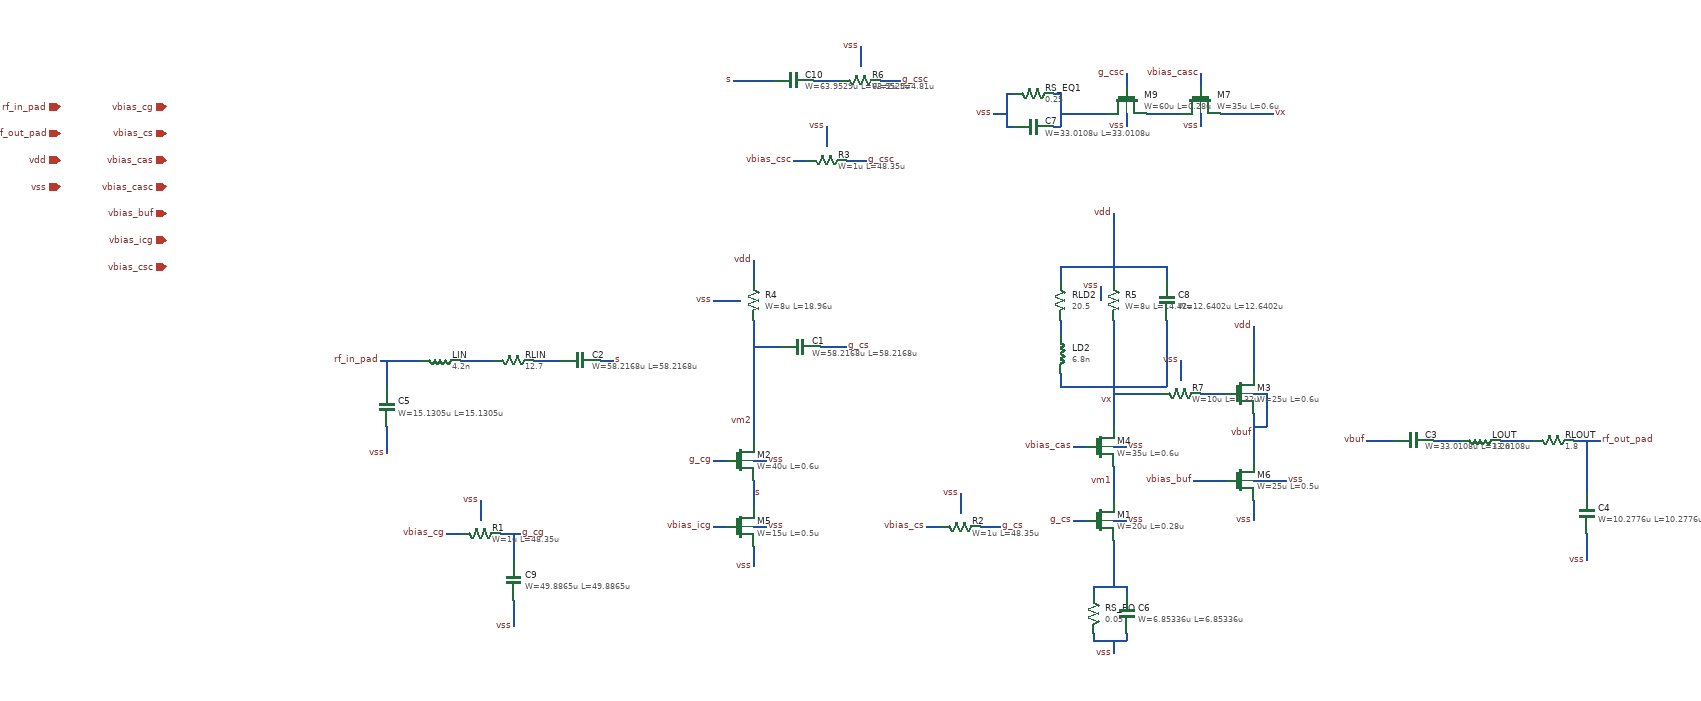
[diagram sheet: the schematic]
v {xschem version=3.4.8RC file_version=1.3}
G {}
K {}
V {}
S {}
F {}
E {}
N 700 -330 720 -330 {
lab=vss}
N 700 -540 700 -460 {
lab=vm2}
N 700 -630 700 -600 {
lab=vdd}
N 470 -480 490 -480 {
lab=s}
N 140 -480 170 -480 {
lab=rf_in_pad}
N 700 -500 740 -500 {
lab=vm2}
N 800 -500 840 -500 {
lab=g_cs}
N 700 -300 700 -290 {
lab=s}
N 700 -290 700 -260 {
lab=s}
N 640 -330 660 -330 {
lab=g_cg}
N 240 -220 260 -220 {
lab=vbias_cg}
N 320 -220 350 -220 {
lab=g_cg}
N 340 -120 340 -80 {
lab=vss}
N 1240 -240 1260 -240 {
lab=vss}
N 1240 -210 1240 -200 {
lab=#net1}
N 1180 -240 1200 -240 {
lab=g_cs}
N 960 -230 980 -230 {
lab=vbias_cs}
N 1040 -230 1070 -230 {
lab=g_cs}
N 1240 -200 1240 -140 {
lab=#net1}
N 1240 -640 1240 -600 {
lab=vdd}
N 1450 -530 1450 -460 {
lab=vdd}
N 1450 -400 1450 -330 {
lab=vbuf}
N 1450 -270 1450 -240 {
lab=vss}
N 1450 -430 1470 -430 {
lab=vbuf}
N 1620 -360 1660 -360 {
lab=vbuf}
N 1720 -360 1760 -360 {
lab=#net2}
N 1820 -360 1870 -360 {
lab=#net3}
N 1930 -360 1970 -360 {
lab=rf_out_pad}
N 1950 -360 1950 -280 {
lab=rf_out_pad}
N 1950 -220 1950 -180 {
lab=vss}
N 150 -480 150 -440 {
lab=rf_in_pad}
N 150 -380 150 -340 {
lab=vss}
N 170 -480 200 -480 {
lab=rf_in_pad}
N 260 -480 310 -480 {
lab=#net4}
N 370 -480 410 -480 {
lab=#net5}
N 1240 -350 1260 -350 {
lab=vss}
N 1240 -320 1240 -310 {
lab=vm1}
N 1180 -350 1200 -350 {
lab=vbias_cas}
N 1240 -540 1240 -460 {
lab=vx}
N 1240 -310 1240 -270 {
lab=vm1}
N 1470 -430 1470 -380 {
lab=vbuf}
N 1450 -380 1470 -380 {
lab=vbuf}
N 700 -230 720 -230 {
lab=vss}
N 700 -200 700 -190 {
lab=vss}
N 640 -230 660 -230 {
lab=vbias_icg}
N 700 -190 700 -170 {
lab=vss}
N 1360 -300 1410 -300 {
lab=vbias_buf}
N 1450 -300 1500 -300 {
lab=vss}
N 1260 -140 1260 -130 {
lab=#net1}
N 1210 -140 1260 -140 {
lab=#net1}
N 1260 -70 1260 -60 {
lab=vss}
N 1210 -60 1260 -60 {
lab=vss}
N 1210 -140 1210 -130 {
lab=#net1}
N 1210 -70 1210 -60 {
lab=vss}
N 1240 -60 1240 -40 {
lab=vss}
N 1370 -430 1410 -430 {
lab=#net6}
N 1240 -430 1310 -430 {
lab=vx}
N 1260 -850 1260 -830 {
lab=vss}
N 1220 -850 1230 -850 {
lab=#net7}
N 1260 -910 1260 -890 {
lab=g_csc}
N 760 -780 780 -780 {
lab=vbias_csc}
N 840 -780 870 -780 {
lab=g_csc}
N 1160 -850 1220 -850 {
lab=#net7}
N 1370 -850 1370 -830 {
lab=vss}
N 1330 -850 1340 -850 {
lab=#net8}
N 1370 -910 1370 -890 {
lab=vbias_casc}
N 1400 -850 1480 -850 {
lab=vx}
N 1290 -850 1330 -850 {
lab=#net8}
N 1150 -830 1160 -830 {
lab=#net7}
N 1160 -880 1160 -830 {
lab=#net7}
N 1080 -830 1090 -830 {
lab=vss}
N 1080 -880 1080 -830 {
lab=vss}
N 1150 -880 1160 -880 {
lab=#net7}
N 1080 -880 1090 -880 {
lab=vss}
N 1060 -850 1080 -850 {
lab=vss}
N 790 -900 830 -900 {
lab=#net9
}
N 700 -400 700 -390 {
lab=vm2}
N 700 -390 700 -360 {lab=vm2}
N 1160 -620 1160 -600 {lab=vdd}
N 1160 -620 1240 -620 {lab=vdd}
N 1160 -540 1160 -520 {lab=#net10}
N 1320 -540 1320 -530 {lab=vx}
N 1240 -440 1320 -440 {lab=vx}
N 1320 -620 1320 -600 {lab=vdd}
N 1240 -620 1320 -620 {lab=vdd}
N 1320 -530 1320 -520 {lab=vx}
N 700 -460 700 -400 {lab=vm2}
N 1240 -460 1240 -380 {lab=vx}
N 1160 -460 1160 -440 {lab=vx}
N 1160 -440 1240 -440 {lab=vx}
N 1320 -520 1320 -440 {lab=vx}
N 890 -900 920 -900 {lab=g_csc
}
N 1010 -280 1010 -250 {lab=vss}
N 810 -830 810 -800 {lab=#net11}
N 290 -270 290 -240 {lab=vss}
N 640 -570 680 -570 {lab=vss}
N 1220 -590 1220 -570 {lab=vss}
N 1240 -700 1240 -640 {lab=vdd}
N 860 -950 860 -920 {lab=vss
}
N 1340 -480 1340 -450 {lab=vss}
N 340 -220 340 -180 {lab=g_cg}
N 670 -900 730 -900 {lab=s
}
C {lab_pin.sym} 700 -630 0 0 {name=p11 sig_type=std_logic lab=vdd
}
C {lab_pin.sym} 840 -500 2 0 {name=p14 sig_type=std_logic lab=g_cs}
C {lab_pin.sym} 700 -280 2 0 {name=p1 sig_type=std_logic lab=s}
C {symbols/nfet_06v0.sym} 680 -330 0 0 {name=M2
L=0.6u
W=40u
nf=10
m=14
ad="'int((nf+1)/2) * W/nf * 0.18u'"
pd="'2*int((nf+1)/2) * (W/nf + 0.18u)'"
as="'int((nf+2)/2) * W/nf * 0.18u'"
ps="'2*int((nf+2)/2) * (W/nf + 0.18u)'"
nrd="'0.18u / W'" nrs="'0.18u / W'"
sa=0 sb=0 sd=0
model=nfet_06v0
spiceprefix=X
}
C {lab_pin.sym} 490 -480 2 0 {name=p17 sig_type=std_logic lab=s}
C {lab_pin.sym} 240 -220 0 0 {name=p20 sig_type=std_logic lab=vbias_cg}
C {lab_pin.sym} 350 -220 2 0 {name=p21 sig_type=std_logic lab=g_cg}
C {lab_pin.sym} 140 -480 0 0 {name=p13 sig_type=std_logic lab=rf_in_pad}
C {lab_pin.sym} 640 -330 0 0 {name=p4 sig_type=std_logic lab=g_cg}
C {lab_pin.sym} 1180 -240 0 0 {name=p18 sig_type=std_logic lab=g_cs}
C {lab_pin.sym} 960 -230 0 0 {name=p23 sig_type=std_logic lab=vbias_cs}
C {lab_pin.sym} 1070 -230 2 0 {name=p24 sig_type=std_logic lab=g_cs}
C {lab_pin.sym} 1240 -700 0 0 {name=p39 sig_type=std_logic lab=vdd
}
C {symbols/nfet_06v0.sym} 1430 -430 0 0 {name=M3
L=0.6u
W=25u
nf=10
m=10
ad="'int((nf+1)/2) * W/nf * 0.18u'"
pd="'2*int((nf+1)/2) * (W/nf + 0.18u)'"
as="'int((nf+2)/2) * W/nf * 0.18u'"
ps="'2*int((nf+2)/2) * (W/nf + 0.18u)'"
nrd="'0.18u / W'" nrs="'0.18u / W'"
sa=0 sb=0 sd=0
model=nfet_06v0
spiceprefix=X
}
C {lab_pin.sym} 1450 -530 0 0 {name=p40 sig_type=std_logic lab=vdd
}
C {lab_pin.sym} 1450 -370 0 0 {name=p43 sig_type=std_logic lab=vbuf}
C {lab_pin.sym} 1620 -360 0 0 {name=p44 sig_type=std_logic lab=vbuf}
C {lab_pin.sym} 1970 -360 2 0 {name=p45 sig_type=std_logic lab=rf_out_pad}
C {ind.sym} 1790 -360 1 0 {name=LOUT
m=1
value=1.2n
footprint=1206
device=inductor
}
C {res.sym} 1900 -360 1 0 {name=RLOUT
value=1.8
footprint=1206
device=resistor
m=1}
C {lab_pin.sym} 150 -340 3 0 {name=p46 sig_type=std_logic lab=vss}
C {ind.sym} 230 -480 1 0 {name=LIN
m=1
value=4.2n
footprint=1206
device=inductor
}
C {res.sym} 340 -480 1 0 {name=RLIN
value=12.7
footprint=1206
device=resistor
m=1}
C {symbols/nfet_06v0.sym} 1220 -350 0 0 {name=M4
L=0.6u
W=35u
nf=10
m=4
ad="'int((nf+1)/2) * W/nf * 0.18u'"
pd="'2*int((nf+1)/2) * (W/nf + 0.18u)'"
as="'int((nf+2)/2) * W/nf * 0.18u'"
ps="'2*int((nf+2)/2) * (W/nf + 0.18u)'"
nrd="'0.18u / W'" nrs="'0.18u / W'"
sa=0 sb=0 sd=0
model=nfet_06v0
spiceprefix=X
}
C {lab_pin.sym} 1180 -350 0 0 {name=p47 sig_type=std_logic lab=vbias_cas}
C {lab_pin.sym} 640 -230 0 0 {name=p50 sig_type=std_logic lab=vbias_icg}
C {lab_pin.sym} 1360 -300 0 0 {name=p51 sig_type=std_logic lab=vbias_buf}
C {symbols/nfet_03v3.sym} 680 -230 0 0 {name=M5
L=0.5u
W=15u
nf=10
m=1
ad="'int((nf+1)/2) * W/nf * 0.18u'"
pd="'2*int((nf+1)/2) * (W/nf + 0.18u)'"
as="'int((nf+2)/2) * W/nf * 0.18u'"
ps="'2*int((nf+2)/2) * (W/nf + 0.18u)'"
nrd="'0.18u / W'" nrs="'0.18u / W'"
sa=0 sb=0 sd=0
model=nfet_03v3
spiceprefix=X
}
C {symbols/nfet_03v3.sym} 1430 -300 0 0 {name=M6
L=0.5u
W=25u
nf=10
m=5
ad="'int((nf+1)/2) * W/nf * 0.18u'"
pd="'2*int((nf+1)/2) * (W/nf + 0.18u)'"
as="'int((nf+2)/2) * W/nf * 0.18u'"
ps="'2*int((nf+2)/2) * (W/nf + 0.18u)'"
nrd="'0.18u / W'" nrs="'0.18u / W'"
sa=0 sb=0 sd=0
model=nfet_03v3
spiceprefix=X
}
C {res.sym} 1210 -100 0 0 {name=RS_EQ
value=0.05
footprint=1206
device=resistor
m=1
}
C {symbols/nfet_03v3.sym} 1220 -240 0 0 {name=M1
L=0.28u
W=20u
nf=10
m=10
ad="'int((nf+1)/2) * W/nf * 0.18u'"
pd="'2*int((nf+1)/2) * (W/nf + 0.18u)'"
as="'int((nf+2)/2) * W/nf * 0.18u'"
ps="'2*int((nf+2)/2) * (W/nf + 0.18u)'"
nrd="'0.18u / W'" nrs="'0.18u / W'"
sa=0 sb=0 sd=0
model=nfet_03v3
spiceprefix=X
}
C {lab_pin.sym} 1260 -910 1 0 {name=p28 sig_type=std_logic lab=g_csc}
C {lab_pin.sym} 760 -780 0 0 {name=p29 sig_type=std_logic lab=vbias_csc}
C {lab_pin.sym} 870 -780 2 0 {name=p30 sig_type=std_logic lab=g_csc}
C {symbols/nfet_06v0.sym} 1370 -870 1 0 {name=M7
L=0.6u
W=35u
nf=10
m=2
ad="'int((nf+1)/2) * W/nf * 0.18u'"
pd="'2*int((nf+1)/2) * (W/nf + 0.18u)'"
as="'int((nf+2)/2) * W/nf * 0.18u'"
ps="'2*int((nf+2)/2) * (W/nf + 0.18u)'"
nrd="'0.18u / W'" nrs="'0.18u / W'"
sa=0 sb=0 sd=0
model=nfet_06v0
spiceprefix=X
}
C {lab_pin.sym} 1370 -910 1 0 {name=p32 sig_type=std_logic lab=vbias_casc}
C {res.sym} 1120 -880 1 0 {name=RS_EQ1
value=0.25
footprint=1206
device=resistor
m=1
}
C {symbols/nfet_03v3.sym} 1260 -870 1 0 {name=M9
L=0.28u
W=60u
nf=4
m=4
ad="'int((nf+1)/2) * W/nf * 0.18u'"
pd="'2*int((nf+1)/2) * (W/nf + 0.18u)'"
as="'int((nf+2)/2) * W/nf * 0.18u'"
ps="'2*int((nf+2)/2) * (W/nf + 0.18u)'"
nrd="'0.18u / W'" nrs="'0.18u / W'"
sa=0 sb=0 sd=0
model=nfet_03v3
spiceprefix=X
}
C {lab_pin.sym} 1240 -420 0 0 {name=p36 sig_type=std_logic lab=vx}
C {lab_pin.sym} 1480 -850 2 0 {name=p66 sig_type=std_logic lab=vx}
C {lab_pin.sym} 920 -900 2 0 {name=p68 sig_type=std_logic lab=g_csc
}
C {lab_pin.sym} 670 -900 0 0 {name=p69 sig_type=std_logic lab=s
}
C {lab_pin.sym} 700 -388.75 0 0 {name=p71 sig_type=std_logic lab=vm2}
C {lab_pin.sym} 1240 -298.75 0 0 {name=p72 sig_type=std_logic lab=vm1}
C {ind.sym} 1160 -490 0 0 {name=LD2
m=1
value=6.8n
footprint=1206
device=inductor
}
C {res.sym} 1160 -570 0 0 {name=RLD2
value=20.5
footprint=1206
device=resistor
m=1
}
C {symbols/ppolyf_u_1k.sym} 1010 -230 1 0 {name=R2
W=1u
L=48.35u
model=ppolyf_u_1k
spiceprefix=X
m=1}
C {symbols/ppolyf_u_1k.sym} 810 -780 1 0 {name=R3
W=1u
L=48.35u
model=ppolyf_u_1k
spiceprefix=X
m=1}
C {symbols/ppolyf_u_1k.sym} 290 -220 1 0 {name=R1
W=1u
L=48.35u
model=ppolyf_u_1k
spiceprefix=X
m=1}
C {symbols/ppolyf_u.sym} 700 -570 0 0 {name=R4
W=8u
L=18.96u
model=ppolyf_u
spiceprefix=X
m=1}
C {symbols/ppolyf_u.sym} 1240 -570 0 0 {name=R5
W=8u
L=14.42u
model=ppolyf_u
spiceprefix=X
m=1}
C {symbols/npolyf_s.sym} 860 -900 1 0 {name=R6
W=2u
L=4.81u
model=npolyf_s
spiceprefix=X
m=1
}
C {symbols/npolyf_s.sym} 1340 -430 1 0 {name=R7
W=10u
L=1.32u
model=npolyf_s
spiceprefix=X
m=1}
C {symbols/cap_mim_2f0fF.sym} 770 -500 1 0 {name=C1
W=58.2168u
L=58.2168u
model=cap_mim_2f0_m4m5_noshield
spiceprefix=X
m=1}
C {symbols/cap_mim_2f0fF.sym} 440 -480 1 0 {name=C2
W=58.2168u
L=58.2168u
model=cap_mim_2f0_m4m5_noshield
spiceprefix=X
m=1}
C {symbols/cap_mim_2f0fF.sym} 1690 -360 1 0 {name=C3
W=33.0108u
L=33.0108u
model=cap_mim_2f0_m4m5_noshield
spiceprefix=X
m=1}
C {symbols/cap_mim_2f0fF.sym} 1950 -250 0 0 {name=C4
W=10.2776u
L=10.2776u
model=cap_mim_2f0_m4m5_noshield
spiceprefix=X
m=1}
C {symbols/cap_mim_2f0fF.sym} 150 -410 0 0 {name=C5
W=15.1305u
L=15.1305u
model=cap_mim_2f0_m4m5_noshield
spiceprefix=X
m=1}
C {symbols/cap_mim_2f0fF.sym} 1260 -100 0 0 {name=C6
W=6.85336u
L=6.85336u
model=cap_mim_2f0_m4m5_noshield
spiceprefix=X
m=1}
C {symbols/cap_mim_2f0fF.sym} 1120 -830 1 0 {name=C7
W=33.0108u
L=33.0108u
model=cap_mim_2f0_m4m5_noshield
spiceprefix=X
m=1}
C {symbols/cap_mim_2f0fF.sym} 1320 -570 0 0 {name=C8
W=12.6402u
L=12.6402u
model=cap_mim_2f0_m4m5_noshield
spiceprefix=X
m=1}
C {symbols/cap_mim_2f0fF.sym} 340 -150 2 1 {name=C9
W=49.8865u
L=49.8865u
model=cap_mim_2f0_m4m5_noshield
spiceprefix=X
m=4}
C {symbols/cap_mim_2f0fF.sym} 760 -900 3 0 {name=C10
W=63.9529u
L=63.9529u
model=cap_mim_2f0_m4m5_noshield
spiceprefix=X
m=1
}
C {iopin.sym} -340 -860 0 0 {name=p56 lab=rf_in_pad}
C {iopin.sym} -180 -860 0 0 {name=p57 lab=vbias_cg}
C {iopin.sym} -340 -820 0 0 {name=p58 lab=rf_out_pad}
C {iopin.sym} -180 -820 0 0 {name=p59 lab=vbias_cs
}
C {iopin.sym} -340 -780 0 0 {name=p60 lab=vdd}
C {iopin.sym} -180 -780 0 0 {name=p61 lab=vbias_cas}
C {iopin.sym} -340 -740 0 0 {name=p62 lab=vss}
C {iopin.sym} -180 -740 0 0 {name=p63 lab=vbias_casc}
C {iopin.sym} -180 -700 0 0 {name=p64 lab=vbias_buf}
C {iopin.sym} -180 -660 0 0 {name=p65 lab=vbias_icg}
C {iopin.sym} -180 -620 0 0 {name=p79 lab=vbias_csc}
C {lab_pin.sym} 700 -170 3 0 {name=p5 sig_type=std_logic lab=vss}
C {lab_pin.sym} 1060 -850 0 0 {name=p6 sig_type=std_logic lab=vss}
C {lab_pin.sym} 1240 -40 3 0 {name=p7 sig_type=std_logic lab=vss}
C {lab_pin.sym} 1450 -240 3 0 {name=p8 sig_type=std_logic lab=vss}
C {lab_pin.sym} 1950 -180 3 0 {name=p9 sig_type=std_logic lab=vss}
C {lab_pin.sym} 340 -80 3 0 {name=p10 sig_type=std_logic lab=vss}
C {lab_pin.sym} 720 -230 2 0 {name=p2 sig_type=std_logic lab=vss}
C {lab_pin.sym} 720 -330 2 0 {name=p12 sig_type=std_logic lab=vss}
C {lab_pin.sym} 640 -570 0 0 {name=p16 sig_type=std_logic lab=vss}
C {lab_pin.sym} 810 -830 1 0 {name=p19 sig_type=std_logic lab=vss
spice_ignore=true}
C {lab_pin.sym} 1260 -830 3 0 {name=p26 sig_type=std_logic lab=vss}
C {lab_pin.sym} 1370 -830 3 0 {name=p27 sig_type=std_logic lab=vss}
C {lab_pin.sym} 290 -270 1 0 {name=p3 sig_type=std_logic lab=vss}
C {lab_pin.sym} 1010 -280 1 0 {name=p31 sig_type=std_logic lab=vss}
C {lab_pin.sym} 860 -950 1 0 {name=p33 sig_type=std_logic lab=vss
}
C {lab_pin.sym} 1220 -590 1 0 {name=p34 sig_type=std_logic lab=vss}
C {lab_pin.sym} 1340 -480 1 0 {name=p35 sig_type=std_logic lab=vss}
C {lab_pin.sym} 1260 -350 2 0 {name=p41 sig_type=std_logic lab=vss}
C {lab_pin.sym} 1260 -240 2 0 {name=p42 sig_type=std_logic lab=vss}
C {lab_pin.sym} 1500 -300 2 0 {name=p48 sig_type=std_logic lab=vss}
